VERSION 5.8 ;
BUSBITCHARS "[]" ;
DIVIDERCHAR "/" ;
UNITS
    DATABASE MICRONS 1000 ;
END UNITS

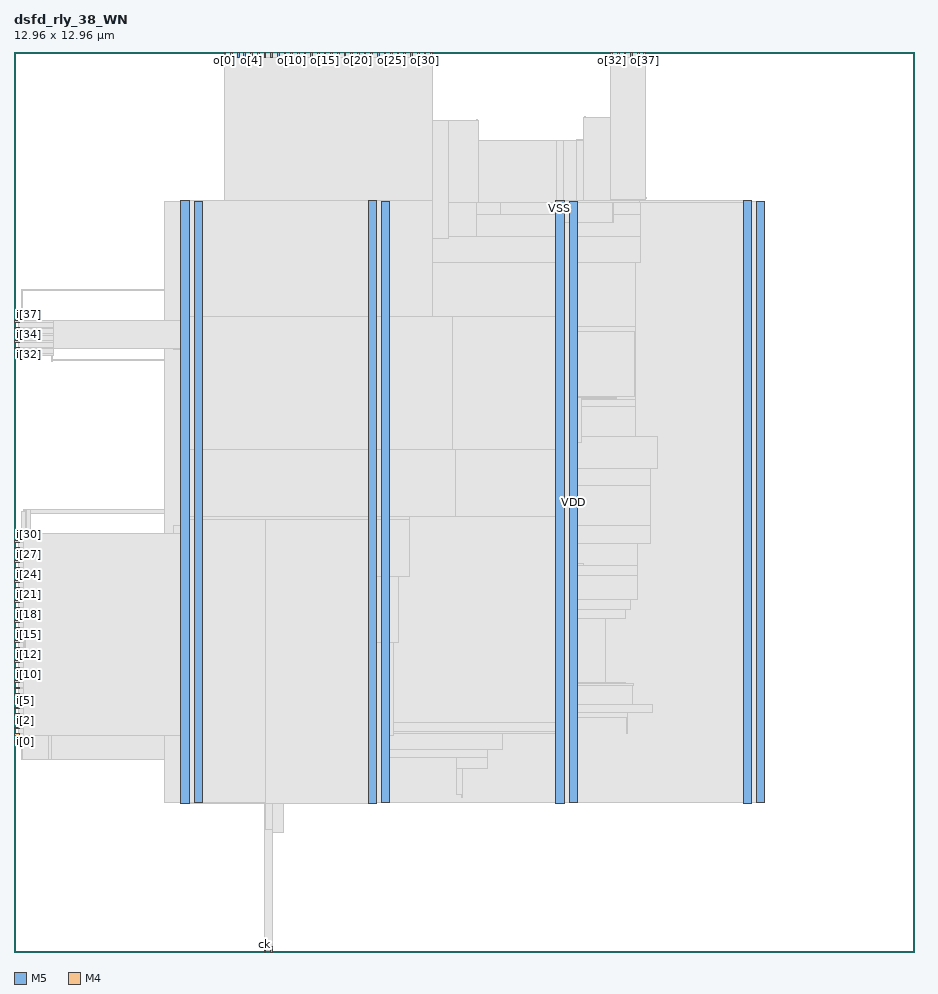
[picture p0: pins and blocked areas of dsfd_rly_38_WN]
MACRO dsfd_rly_38_WN
  FOREIGN dsfd_rly_38_WN 0 0 ;
  CLASS BLOCK ;
  SIZE 12.96 BY 12.96 ;
  PIN ck
    DIRECTION INPUT ;
    USE SIGNAL ;
    PORT
      LAYER M5 ;
        RECT  3.6 0 3.624 0.084 ;
    END
  END ck
  PIN i[0]
    DIRECTION INPUT ;
    USE SIGNAL ;
    PORT
      LAYER M4 ;
        RECT  0 3.024 0.084 3.048 ;
    END
  END i[0]
  PIN i[10]
    DIRECTION INPUT ;
    USE SIGNAL ;
    PORT
      LAYER M4 ;
        RECT  0 3.984 0.084 4.008 ;
    END
  END i[10]
  PIN i[11]
    DIRECTION INPUT ;
    USE SIGNAL ;
    PORT
      LAYER M4 ;
        RECT  0 4.08 0.084 4.104 ;
    END
  END i[11]
  PIN i[12]
    DIRECTION INPUT ;
    USE SIGNAL ;
    PORT
      LAYER M4 ;
        RECT  0 4.176 0.084 4.2 ;
    END
  END i[12]
  PIN i[13]
    DIRECTION INPUT ;
    USE SIGNAL ;
    PORT
      LAYER M4 ;
        RECT  0 4.272 0.084 4.296 ;
    END
  END i[13]
  PIN i[14]
    DIRECTION INPUT ;
    USE SIGNAL ;
    PORT
      LAYER M4 ;
        RECT  0 4.368 0.084 4.392 ;
    END
  END i[14]
  PIN i[15]
    DIRECTION INPUT ;
    USE SIGNAL ;
    PORT
      LAYER M4 ;
        RECT  0 4.464 0.084 4.488 ;
    END
  END i[15]
  PIN i[16]
    DIRECTION INPUT ;
    USE SIGNAL ;
    PORT
      LAYER M4 ;
        RECT  0 4.56 0.084 4.584 ;
    END
  END i[16]
  PIN i[17]
    DIRECTION INPUT ;
    USE SIGNAL ;
    PORT
      LAYER M4 ;
        RECT  0 4.656 0.084 4.68 ;
    END
  END i[17]
  PIN i[18]
    DIRECTION INPUT ;
    USE SIGNAL ;
    PORT
      LAYER M4 ;
        RECT  0 4.752 0.084 4.776 ;
    END
  END i[18]
  PIN i[19]
    DIRECTION INPUT ;
    USE SIGNAL ;
    PORT
      LAYER M4 ;
        RECT  0 4.848 0.084 4.872 ;
    END
  END i[19]
  PIN i[1]
    DIRECTION INPUT ;
    USE SIGNAL ;
    PORT
      LAYER M4 ;
        RECT  0 3.12 0.084 3.144 ;
    END
  END i[1]
  PIN i[20]
    DIRECTION INPUT ;
    USE SIGNAL ;
    PORT
      LAYER M4 ;
        RECT  0 4.944 0.084 4.968 ;
    END
  END i[20]
  PIN i[21]
    DIRECTION INPUT ;
    USE SIGNAL ;
    PORT
      LAYER M4 ;
        RECT  0 5.04 0.084 5.064 ;
    END
  END i[21]
  PIN i[22]
    DIRECTION INPUT ;
    USE SIGNAL ;
    PORT
      LAYER M4 ;
        RECT  0 5.136 0.084 5.16 ;
    END
  END i[22]
  PIN i[23]
    DIRECTION INPUT ;
    USE SIGNAL ;
    PORT
      LAYER M4 ;
        RECT  0 5.232 0.084 5.256 ;
    END
  END i[23]
  PIN i[24]
    DIRECTION INPUT ;
    USE SIGNAL ;
    PORT
      LAYER M4 ;
        RECT  0 5.328 0.084 5.352 ;
    END
  END i[24]
  PIN i[25]
    DIRECTION INPUT ;
    USE SIGNAL ;
    PORT
      LAYER M4 ;
        RECT  0 5.424 0.084 5.448 ;
    END
  END i[25]
  PIN i[26]
    DIRECTION INPUT ;
    USE SIGNAL ;
    PORT
      LAYER M4 ;
        RECT  0 5.52 0.084 5.544 ;
    END
  END i[26]
  PIN i[27]
    DIRECTION INPUT ;
    USE SIGNAL ;
    PORT
      LAYER M4 ;
        RECT  0 5.616 0.084 5.64 ;
    END
  END i[27]
  PIN i[28]
    DIRECTION INPUT ;
    USE SIGNAL ;
    PORT
      LAYER M4 ;
        RECT  0 5.712 0.084 5.736 ;
    END
  END i[28]
  PIN i[29]
    DIRECTION INPUT ;
    USE SIGNAL ;
    PORT
      LAYER M4 ;
        RECT  0 5.808 0.084 5.832 ;
    END
  END i[29]
  PIN i[2]
    DIRECTION INPUT ;
    USE SIGNAL ;
    PORT
      LAYER M4 ;
        RECT  0 3.216 0.084 3.24 ;
    END
  END i[2]
  PIN i[30]
    DIRECTION INPUT ;
    USE SIGNAL ;
    PORT
      LAYER M4 ;
        RECT  0 5.904 0.084 5.928 ;
    END
  END i[30]
  PIN i[31]
    DIRECTION INPUT ;
    USE SIGNAL ;
    PORT
      LAYER M4 ;
        RECT  0 6 0.084 6.024 ;
    END
  END i[31]
  PIN i[32]
    DIRECTION INPUT ;
    USE SIGNAL ;
    PORT
      LAYER M4 ;
        RECT  0 8.592 0.084 8.616 ;
    END
  END i[32]
  PIN i[33]
    DIRECTION INPUT ;
    USE SIGNAL ;
    PORT
      LAYER M4 ;
        RECT  0 8.688 0.084 8.712 ;
    END
  END i[33]
  PIN i[34]
    DIRECTION INPUT ;
    USE SIGNAL ;
    PORT
      LAYER M4 ;
        RECT  0 8.784 0.084 8.808 ;
    END
  END i[34]
  PIN i[35]
    DIRECTION INPUT ;
    USE SIGNAL ;
    PORT
      LAYER M4 ;
        RECT  0 8.88 0.084 8.904 ;
    END
  END i[35]
  PIN i[36]
    DIRECTION INPUT ;
    USE SIGNAL ;
    PORT
      LAYER M4 ;
        RECT  0 8.976 0.084 9 ;
    END
  END i[36]
  PIN i[37]
    DIRECTION INPUT ;
    USE SIGNAL ;
    PORT
      LAYER M4 ;
        RECT  0 9.072 0.084 9.096 ;
    END
  END i[37]
  PIN i[3]
    DIRECTION INPUT ;
    USE SIGNAL ;
    PORT
      LAYER M4 ;
        RECT  0 3.312 0.084 3.336 ;
    END
  END i[3]
  PIN i[4]
    DIRECTION INPUT ;
    USE SIGNAL ;
    PORT
      LAYER M4 ;
        RECT  0 3.408 0.084 3.432 ;
    END
  END i[4]
  PIN i[5]
    DIRECTION INPUT ;
    USE SIGNAL ;
    PORT
      LAYER M4 ;
        RECT  0 3.504 0.084 3.528 ;
    END
  END i[5]
  PIN i[6]
    DIRECTION INPUT ;
    USE SIGNAL ;
    PORT
      LAYER M4 ;
        RECT  0 3.6 0.084 3.624 ;
    END
  END i[6]
  PIN i[7]
    DIRECTION INPUT ;
    USE SIGNAL ;
    PORT
      LAYER M4 ;
        RECT  0 3.696 0.084 3.72 ;
    END
  END i[7]
  PIN i[8]
    DIRECTION INPUT ;
    USE SIGNAL ;
    PORT
      LAYER M4 ;
        RECT  0 3.792 0.084 3.816 ;
    END
  END i[8]
  PIN i[9]
    DIRECTION INPUT ;
    USE SIGNAL ;
    PORT
      LAYER M4 ;
        RECT  0 3.888 0.084 3.912 ;
    END
  END i[9]
  PIN o[0]
    DIRECTION OUTPUT ;
    USE SIGNAL ;
    PORT
      LAYER M5 ;
        RECT  3.024 12.876 3.048 12.96 ;
    END
  END o[0]
  PIN o[10]
    DIRECTION OUTPUT ;
    USE SIGNAL ;
    PORT
      LAYER M5 ;
        RECT  3.984 12.876 4.008 12.96 ;
    END
  END o[10]
  PIN o[11]
    DIRECTION OUTPUT ;
    USE SIGNAL ;
    PORT
      LAYER M5 ;
        RECT  4.08 12.876 4.104 12.96 ;
    END
  END o[11]
  PIN o[12]
    DIRECTION OUTPUT ;
    USE SIGNAL ;
    PORT
      LAYER M5 ;
        RECT  4.176 12.876 4.2 12.96 ;
    END
  END o[12]
  PIN o[13]
    DIRECTION OUTPUT ;
    USE SIGNAL ;
    PORT
      LAYER M5 ;
        RECT  4.272 12.876 4.296 12.96 ;
    END
  END o[13]
  PIN o[14]
    DIRECTION OUTPUT ;
    USE SIGNAL ;
    PORT
      LAYER M5 ;
        RECT  4.368 12.876 4.392 12.96 ;
    END
  END o[14]
  PIN o[15]
    DIRECTION OUTPUT ;
    USE SIGNAL ;
    PORT
      LAYER M5 ;
        RECT  4.464 12.876 4.488 12.96 ;
    END
  END o[15]
  PIN o[16]
    DIRECTION OUTPUT ;
    USE SIGNAL ;
    PORT
      LAYER M5 ;
        RECT  4.56 12.876 4.584 12.96 ;
    END
  END o[16]
  PIN o[17]
    DIRECTION OUTPUT ;
    USE SIGNAL ;
    PORT
      LAYER M5 ;
        RECT  4.656 12.876 4.68 12.96 ;
    END
  END o[17]
  PIN o[18]
    DIRECTION OUTPUT ;
    USE SIGNAL ;
    PORT
      LAYER M5 ;
        RECT  4.752 12.876 4.776 12.96 ;
    END
  END o[18]
  PIN o[19]
    DIRECTION OUTPUT ;
    USE SIGNAL ;
    PORT
      LAYER M5 ;
        RECT  4.848 12.876 4.872 12.96 ;
    END
  END o[19]
  PIN o[1]
    DIRECTION OUTPUT ;
    USE SIGNAL ;
    PORT
      LAYER M5 ;
        RECT  3.12 12.876 3.144 12.96 ;
    END
  END o[1]
  PIN o[20]
    DIRECTION OUTPUT ;
    USE SIGNAL ;
    PORT
      LAYER M5 ;
        RECT  4.944 12.876 4.968 12.96 ;
    END
  END o[20]
  PIN o[21]
    DIRECTION OUTPUT ;
    USE SIGNAL ;
    PORT
      LAYER M5 ;
        RECT  5.04 12.876 5.064 12.96 ;
    END
  END o[21]
  PIN o[22]
    DIRECTION OUTPUT ;
    USE SIGNAL ;
    PORT
      LAYER M5 ;
        RECT  5.136 12.876 5.16 12.96 ;
    END
  END o[22]
  PIN o[23]
    DIRECTION OUTPUT ;
    USE SIGNAL ;
    PORT
      LAYER M5 ;
        RECT  5.232 12.876 5.256 12.96 ;
    END
  END o[23]
  PIN o[24]
    DIRECTION OUTPUT ;
    USE SIGNAL ;
    PORT
      LAYER M5 ;
        RECT  5.328 12.876 5.352 12.96 ;
    END
  END o[24]
  PIN o[25]
    DIRECTION OUTPUT ;
    USE SIGNAL ;
    PORT
      LAYER M5 ;
        RECT  5.424 12.876 5.448 12.96 ;
    END
  END o[25]
  PIN o[26]
    DIRECTION OUTPUT ;
    USE SIGNAL ;
    PORT
      LAYER M5 ;
        RECT  5.52 12.876 5.544 12.96 ;
    END
  END o[26]
  PIN o[27]
    DIRECTION OUTPUT ;
    USE SIGNAL ;
    PORT
      LAYER M5 ;
        RECT  5.616 12.876 5.64 12.96 ;
    END
  END o[27]
  PIN o[28]
    DIRECTION OUTPUT ;
    USE SIGNAL ;
    PORT
      LAYER M5 ;
        RECT  5.712 12.876 5.736 12.96 ;
    END
  END o[28]
  PIN o[29]
    DIRECTION OUTPUT ;
    USE SIGNAL ;
    PORT
      LAYER M5 ;
        RECT  5.808 12.876 5.832 12.96 ;
    END
  END o[29]
  PIN o[2]
    DIRECTION OUTPUT ;
    USE SIGNAL ;
    PORT
      LAYER M5 ;
        RECT  3.216 12.876 3.24 12.96 ;
    END
  END o[2]
  PIN o[30]
    DIRECTION OUTPUT ;
    USE SIGNAL ;
    PORT
      LAYER M5 ;
        RECT  5.904 12.876 5.928 12.96 ;
    END
  END o[30]
  PIN o[31]
    DIRECTION OUTPUT ;
    USE SIGNAL ;
    PORT
      LAYER M5 ;
        RECT  6 12.876 6.024 12.96 ;
    END
  END o[31]
  PIN o[32]
    DIRECTION OUTPUT ;
    USE SIGNAL ;
    PORT
      LAYER M5 ;
        RECT  8.592 12.876 8.616 12.96 ;
    END
  END o[32]
  PIN o[33]
    DIRECTION OUTPUT ;
    USE SIGNAL ;
    PORT
      LAYER M5 ;
        RECT  8.688 12.876 8.712 12.96 ;
    END
  END o[33]
  PIN o[34]
    DIRECTION OUTPUT ;
    USE SIGNAL ;
    PORT
      LAYER M5 ;
        RECT  8.784 12.876 8.808 12.96 ;
    END
  END o[34]
  PIN o[35]
    DIRECTION OUTPUT ;
    USE SIGNAL ;
    PORT
      LAYER M5 ;
        RECT  8.88 12.876 8.904 12.96 ;
    END
  END o[35]
  PIN o[36]
    DIRECTION OUTPUT ;
    USE SIGNAL ;
    PORT
      LAYER M5 ;
        RECT  8.976 12.876 9 12.96 ;
    END
  END o[36]
  PIN o[37]
    DIRECTION OUTPUT ;
    USE SIGNAL ;
    PORT
      LAYER M5 ;
        RECT  9.072 12.876 9.096 12.96 ;
    END
  END o[37]
  PIN o[3]
    DIRECTION OUTPUT ;
    USE SIGNAL ;
    PORT
      LAYER M5 ;
        RECT  3.312 12.876 3.336 12.96 ;
    END
  END o[3]
  PIN o[4]
    DIRECTION OUTPUT ;
    USE SIGNAL ;
    PORT
      LAYER M5 ;
        RECT  3.408 12.876 3.432 12.96 ;
    END
  END o[4]
  PIN o[5]
    DIRECTION OUTPUT ;
    USE SIGNAL ;
    PORT
      LAYER M5 ;
        RECT  3.504 12.876 3.528 12.96 ;
    END
  END o[5]
  PIN o[6]
    DIRECTION OUTPUT ;
    USE SIGNAL ;
    PORT
      LAYER M5 ;
        RECT  3.6 12.876 3.624 12.96 ;
    END
  END o[6]
  PIN o[7]
    DIRECTION OUTPUT ;
    USE SIGNAL ;
    PORT
      LAYER M5 ;
        RECT  3.696 12.876 3.72 12.96 ;
    END
  END o[7]
  PIN o[8]
    DIRECTION OUTPUT ;
    USE SIGNAL ;
    PORT
      LAYER M5 ;
        RECT  3.792 12.876 3.816 12.96 ;
    END
  END o[8]
  PIN o[9]
    DIRECTION OUTPUT ;
    USE SIGNAL ;
    PORT
      LAYER M5 ;
        RECT  3.888 12.876 3.912 12.96 ;
    END
  END o[9]
  PIN rs
    DIRECTION INPUT ;
    USE SIGNAL ;
    PORT
      LAYER M5 ;
        RECT  3.696 0 3.72 0.084 ;
    END
  END rs
  PIN VDD
    DIRECTION INOUT ;
    USE POWER ;
    PORT
      LAYER M5 ;
        RECT  10.692 2.151 10.812 10.809 ;
        RECT  7.992 2.151 8.112 10.809 ;
        RECT  5.292 2.151 5.412 10.809 ;
        RECT  2.592 2.151 2.712 10.809 ;
    END
  END VDD
  PIN VSS
    DIRECTION INOUT ;
    USE GROUND ;
    PORT
      LAYER M5 ;
        RECT  10.5 2.137 10.62 10.823 ;
        RECT  7.8 2.137 7.92 10.823 ;
        RECT  5.1 2.137 5.22 10.823 ;
        RECT  2.4 2.137 2.52 10.823 ;
    END
  END VSS
  # OT_OBS_CLOSED layer=M5 d_um=1.536 added=7
  OBS
    LAYER RVTN ;
     RECT  2.16 2.16 10.8 2.295 ;
     RECT  2.16 2.565 10.8 2.835 ;
     RECT  2.16 3.105 10.8 3.375 ;
     RECT  2.16 3.645 10.8 3.915 ;
     RECT  2.16 4.185 10.8 4.455 ;
     RECT  2.16 4.725 10.8 4.995 ;
     RECT  2.16 5.265 10.8 5.535 ;
     RECT  2.16 5.805 10.8 6.075 ;
     RECT  2.16 6.345 10.8 6.615 ;
     RECT  2.16 6.885 10.8 7.155 ;
     RECT  2.16 7.425 10.8 7.695 ;
     RECT  2.16 7.965 10.8 8.235 ;
     RECT  2.16 8.505 10.8 8.775 ;
     RECT  2.16 9.045 10.8 9.315 ;
     RECT  2.16 9.585 10.8 9.855 ;
     RECT  2.16 10.125 10.8 10.395 ;
     RECT  2.16 10.665 10.8 10.8 ;
    LAYER RVTP ;
     RECT  2.16 2.295 10.8 2.565 ;
     RECT  2.16 2.835 10.8 3.105 ;
     RECT  2.16 3.375 10.8 3.645 ;
     RECT  2.16 3.915 10.8 4.185 ;
     RECT  2.16 4.455 10.8 4.725 ;
     RECT  2.16 4.995 10.8 5.265 ;
     RECT  2.16 5.535 10.8 5.805 ;
     RECT  2.16 6.075 10.8 6.345 ;
     RECT  2.16 6.615 10.8 6.885 ;
     RECT  2.16 7.155 10.8 7.425 ;
     RECT  2.16 7.695 10.8 7.965 ;
     RECT  2.16 8.235 10.8 8.505 ;
     RECT  2.16 8.775 10.8 9.045 ;
     RECT  2.16 9.315 10.8 9.585 ;
     RECT  2.16 9.855 10.8 10.125 ;
     RECT  2.16 10.395 10.8 10.665 ;
    LAYER M1 ;
     RECT  2.16 2.151 10.8 10.809 ;
    LAYER M2 ;
     RECT  0.103 6.318 0.139 6.336 ;
     RECT  0.139 5.616 0.175 6.372 ;
     RECT  0.175 5.202 0.239 6.372 ;
     RECT  0.239 5.202 0.275 5.22 ;
     RECT  0.103 2.772 0.499 3.132 ;
     RECT  0.499 2.772 0.535 3.294 ;
     RECT  0.535 2.772 2.16 3.942 ;
     RECT  0.239 6.318 2.16 6.372 ;
     RECT  0.535 8.514 2.16 8.532 ;
     RECT  0.103 9.522 2.16 9.54 ;
     RECT  2.16 2.151 10.8 10.809 ;
     RECT  10.8 2.421 10.812 10.539 ;
    LAYER M3 ;
     RECT  5.115 2.143 5.205 2.191 ;
     RECT  3.852 1.723 3.87 2.263 ;
     RECT  4.752 2.191 5.205 2.263 ;
     RECT  6.444 2.227 6.462 2.263 ;
     RECT  2.415 2.143 2.505 2.413 ;
     RECT  3.852 2.263 5.205 2.413 ;
     RECT  7.815 2.143 7.905 2.413 ;
     RECT  10.515 2.143 10.605 2.413 ;
     RECT  2.415 2.413 2.697 2.497 ;
     RECT  3.852 2.413 5.397 2.497 ;
     RECT  6.372 2.263 6.462 2.641 ;
     RECT  2.415 2.497 5.397 2.803 ;
     RECT  6.372 2.641 6.822 2.803 ;
     RECT  2.415 2.803 6.822 2.911 ;
     RECT  2.415 2.911 7.038 3.145 ;
     RECT  7.815 2.413 8.097 3.145 ;
     RECT  2.415 3.145 8.097 3.181 ;
     RECT  0.108 2.767 0.126 3.271 ;
     RECT  0.108 3.271 0.522 3.379 ;
     RECT  2.304 3.181 8.097 3.379 ;
     RECT  8.82 3.145 8.838 3.379 ;
     RECT  0.108 3.379 0.558 3.437 ;
     RECT  2.304 3.379 8.838 3.451 ;
     RECT  2.304 3.451 9.198 3.569 ;
     RECT  2.304 3.569 8.91 3.869 ;
     RECT  2.304 3.869 8.802 3.875 ;
     RECT  0.504 3.437 0.558 4.109 ;
     RECT  2.304 3.875 8.514 4.801 ;
     RECT  2.304 4.801 8.802 4.927 ;
     RECT  2.304 4.927 8.874 5.071 ;
     RECT  0.324 4.363 0.342 5.179 ;
     RECT  0.252 5.179 0.342 5.197 ;
     RECT  2.304 5.071 8.982 5.419 ;
     RECT  0.18 5.197 0.342 5.515 ;
     RECT  0.108 5.515 0.342 5.549 ;
     RECT  2.268 5.419 8.982 5.567 ;
     RECT  2.304 5.567 8.982 5.881 ;
     RECT  0.108 5.549 0.27 6.029 ;
     RECT  2.304 5.881 9.162 6.143 ;
     RECT  0.108 6.029 0.162 6.341 ;
     RECT  0.144 6.341 0.162 6.377 ;
     RECT  2.415 6.143 9.162 6.719 ;
     RECT  2.415 6.719 6.894 6.845 ;
     RECT  7.632 6.719 9.162 6.961 ;
     RECT  7.632 6.961 9.27 7.421 ;
     RECT  3.744 6.845 6.894 7.771 ;
     RECT  3.528 7.771 6.894 7.861 ;
     RECT  7.632 7.421 8.946 7.861 ;
     RECT  2.415 6.845 2.697 7.963 ;
     RECT  3.528 7.861 8.946 7.963 ;
     RECT  2.415 7.963 8.946 7.997 ;
     RECT  0.54 8.509 0.558 8.621 ;
     RECT  2.415 7.997 8.097 8.683 ;
     RECT  2.304 8.683 8.097 8.735 ;
     RECT  2.34 8.735 8.097 8.941 ;
     RECT  8.928 7.997 8.946 8.941 ;
     RECT  2.34 8.941 8.946 9.005 ;
     RECT  0.108 8.875 0.126 9.545 ;
     RECT  2.415 9.005 8.946 9.931 ;
     RECT  2.415 9.931 9.018 10.301 ;
     RECT  2.415 10.301 5.814 10.547 ;
     RECT  10.515 2.413 10.797 10.547 ;
     RECT  6.66 10.301 9.018 10.625 ;
     RECT  3.384 10.547 5.814 10.781 ;
     RECT  2.415 10.547 2.505 10.817 ;
     RECT  7.815 10.625 9.018 10.817 ;
     RECT  10.515 10.547 10.605 10.817 ;
     RECT  6.66 10.625 7.002 10.829 ;
     RECT  8.1 10.817 9.018 11.405 ;
     RECT  3.528 10.781 5.814 11.453 ;
     RECT  8.1 11.405 8.55 11.453 ;
     RECT  5.4 11.453 5.418 11.501 ;
     RECT  8.1 11.453 8.226 11.693 ;
     RECT  6.66 10.829 6.678 11.981 ;
     RECT  8.208 11.693 8.226 12.029 ;
     RECT  3.528 11.453 4.59 12.619 ;
     RECT  3.528 12.619 4.95 12.715 ;
     RECT  3.528 12.715 5.094 12.845 ;
    LAYER M4 ;
     RECT  0.084 3.024 0.137 3.048 ;
     RECT  0.06 3.048 0.137 3.12 ;
     RECT  0.084 3.12 0.137 3.144 ;
     RECT  0.06 3.144 0.137 3.216 ;
     RECT  0.084 3.216 0.137 3.24 ;
     RECT  0.06 3.24 0.137 3.312 ;
     RECT  0.084 3.312 0.137 3.336 ;
     RECT  0.06 3.336 0.137 3.408 ;
     RECT  0.084 3.408 0.137 3.432 ;
     RECT  0.06 3.432 0.137 3.504 ;
     RECT  0.084 3.504 0.137 3.528 ;
     RECT  0.06 3.528 0.137 3.6 ;
     RECT  0.084 3.6 0.137 3.624 ;
     RECT  0.06 3.624 0.137 3.696 ;
     RECT  0.084 3.696 0.137 3.72 ;
     RECT  0.06 3.72 0.137 3.792 ;
     RECT  0.084 3.792 0.137 3.816 ;
     RECT  0.06 3.816 0.137 3.888 ;
     RECT  0.084 3.888 0.137 3.912 ;
     RECT  0.06 3.912 0.137 3.984 ;
     RECT  0.084 3.984 0.137 4.008 ;
     RECT  0.06 4.008 0.137 4.08 ;
     RECT  0.084 4.08 0.137 4.104 ;
     RECT  0.06 4.104 0.137 4.176 ;
     RECT  0.084 4.176 0.137 4.2 ;
     RECT  0.06 4.2 0.137 4.272 ;
     RECT  0.084 4.272 0.137 4.296 ;
     RECT  0.06 4.296 0.137 4.368 ;
     RECT  0.084 4.368 0.137 4.392 ;
     RECT  0.06 4.392 0.137 4.464 ;
     RECT  0.084 4.464 0.137 4.488 ;
     RECT  0.06 4.488 0.137 4.56 ;
     RECT  0.084 4.56 0.137 4.584 ;
     RECT  0.06 4.584 0.137 4.656 ;
     RECT  0.084 4.656 0.137 4.68 ;
     RECT  0.06 4.68 0.137 4.752 ;
     RECT  0.084 4.752 0.137 4.776 ;
     RECT  0.06 4.776 0.137 4.848 ;
     RECT  0.084 4.848 0.137 4.872 ;
     RECT  0.06 4.872 0.137 4.944 ;
     RECT  0.084 4.944 0.137 4.968 ;
     RECT  0.06 4.968 0.137 5.04 ;
     RECT  0.084 5.04 0.137 5.064 ;
     RECT  0.06 5.064 0.137 5.136 ;
     RECT  0.084 5.136 0.137 5.16 ;
     RECT  0.06 5.16 0.137 5.232 ;
     RECT  0.084 5.232 0.137 5.256 ;
     RECT  0.06 5.256 0.137 5.328 ;
     RECT  0.084 5.328 0.137 5.352 ;
     RECT  0.06 5.352 0.137 5.424 ;
     RECT  0.084 5.424 0.137 5.448 ;
     RECT  0.06 5.448 0.137 5.52 ;
     RECT  0.084 5.52 0.137 5.544 ;
     RECT  0.06 5.544 0.137 5.616 ;
     RECT  0.084 5.616 0.137 5.64 ;
     RECT  0.06 5.64 0.137 5.712 ;
     RECT  0.084 5.712 0.137 5.736 ;
     RECT  0.06 5.736 0.137 5.808 ;
     RECT  0.084 5.808 0.137 5.832 ;
     RECT  0.06 5.832 0.137 5.904 ;
     RECT  0.084 5.904 0.137 5.928 ;
     RECT  0.06 5.928 0.137 6 ;
     RECT  0.084 6 0.137 6.024 ;
     RECT  0.084 8.592 0.569 8.616 ;
     RECT  0.06 8.616 0.569 8.688 ;
     RECT  0.084 8.688 0.569 8.712 ;
     RECT  0.06 8.712 0.569 8.784 ;
     RECT  0.084 8.784 0.569 8.808 ;
     RECT  0.06 8.808 0.569 8.88 ;
     RECT  0.084 8.88 0.569 8.904 ;
     RECT  0.06 8.904 0.569 8.976 ;
     RECT  0.084 8.976 0.569 9 ;
     RECT  0.06 9 0.569 9.072 ;
     RECT  0.084 9.072 0.569 9.096 ;
     RECT  0.137 3.12 2.408 6.024 ;
     RECT  0.569 8.688 2.408 9.096 ;
     RECT  2.408 2.148 2.512 10.812 ;
     RECT  2.512 2.208 2.704 10.776 ;
     RECT  2.704 10.272 3.589 10.776 ;
     RECT  2.704 2.208 3.685 6.84 ;
     RECT  3.589 10.272 3.74 10.824 ;
     RECT  3.685 1.728 3.881 6.84 ;
     RECT  3.881 2.208 3.913 6.84 ;
     RECT  2.704 7.968 3.913 9.096 ;
     RECT  3.74 10.272 3.973 11.448 ;
     RECT  3.397 12.816 3.973 12.84 ;
     RECT  3.913 2.208 5.108 9.096 ;
     RECT  3.973 10.272 5.108 12.84 ;
     RECT  5.108 2.148 5.126 12.84 ;
     RECT  5.126 2.148 5.212 12.792 ;
     RECT  5.212 2.418 5.404 12.792 ;
     RECT  5.404 3.12 5.465 9.144 ;
     RECT  5.404 10.272 5.699 12.792 ;
     RECT  5.699 10.272 6.257 11.976 ;
     RECT  6.257 10.8 6.689 11.976 ;
     RECT  5.465 3.312 7.808 9.144 ;
     RECT  6.689 10.8 7.808 11.688 ;
     RECT  7.808 2.148 7.912 11.688 ;
     RECT  7.912 2.418 8.104 11.688 ;
     RECT  8.104 7.344 8.165 7.992 ;
     RECT  8.104 10.512 8.197 11.688 ;
     RECT  8.104 5.568 8.201 5.592 ;
     RECT  8.197 10.512 8.627 12.024 ;
     RECT  8.165 7.968 8.669 7.992 ;
     RECT  8.627 10.8 8.723 12.024 ;
     RECT  8.723 10.8 8.819 11.448 ;
     RECT  8.104 3.84 8.921 3.864 ;
     RECT  8.819 10.8 9.029 11.4 ;
     RECT  9.029 10.8 9.037 10.872 ;
     RECT  9.037 10.848 9.107 10.872 ;
     RECT  10.508 2.148 10.612 10.812 ;
     RECT  10.612 2.418 10.804 10.542 ;
    LAYER M5 ;
     RECT  3.624 0.016 3.696 0.084 ;
     RECT  3.6 0.084 3.72 1.763 ;
     RECT  2.4 2.137 2.52 2.151 ;
     RECT  3.6 1.763 3.624 2.151 ;
     RECT  5.1 2.137 5.22 2.151 ;
     RECT  7.8 2.137 7.92 2.151 ;
     RECT  10.5 2.137 10.62 2.151 ;
     RECT  5.1 2.151 5.412 4.453 ;
     RECT  0.144 4.213 0.168 4.499 ;
     RECT  5.1 4.453 5.544 5.413 ;
     RECT  2.4 2.151 3.624 6.229 ;
     RECT  5.1 5.413 5.688 6.229 ;
     RECT  2.4 6.229 5.688 6.277 ;
     RECT  2.4 6.277 6.36 7.235 ;
     RECT  2.4 7.235 6.312 9.155 ;
     RECT  7.8 2.151 8.112 10.501 ;
     RECT  7.8 10.501 8.616 10.789 ;
     RECT  10.5 2.151 10.812 10.809 ;
     RECT  2.4 9.155 6.024 10.823 ;
     RECT  7.8 10.789 9 10.823 ;
     RECT  10.5 10.809 10.62 10.823 ;
     RECT  8.592 10.823 9 10.837 ;
     RECT  3.024 10.823 6.024 12.876 ;
     RECT  3.048 12.876 3.12 12.944 ;
     RECT  3.144 12.876 3.216 12.944 ;
     RECT  3.24 12.876 3.312 12.944 ;
     RECT  3.336 12.876 3.408 12.944 ;
     RECT  3.432 12.876 3.504 12.944 ;
     RECT  3.528 12.876 3.6 12.944 ;
     RECT  3.624 12.876 3.696 12.944 ;
     RECT  3.72 12.876 3.792 12.944 ;
     RECT  3.816 12.876 3.888 12.944 ;
     RECT  3.912 12.876 3.984 12.944 ;
     RECT  4.008 12.876 4.08 12.944 ;
     RECT  4.104 12.876 4.176 12.944 ;
     RECT  4.2 12.876 4.272 12.944 ;
     RECT  4.296 12.876 4.368 12.944 ;
     RECT  4.392 12.876 4.464 12.944 ;
     RECT  4.488 12.876 4.56 12.944 ;
     RECT  4.584 12.876 4.656 12.944 ;
     RECT  4.68 12.876 4.752 12.944 ;
     RECT  4.776 12.876 4.848 12.944 ;
     RECT  4.872 12.876 4.944 12.944 ;
     RECT  4.968 12.876 5.04 12.944 ;
     RECT  5.064 12.876 5.136 12.944 ;
     RECT  5.16 12.876 5.232 12.944 ;
     RECT  5.256 12.876 5.328 12.944 ;
     RECT  5.352 12.876 5.424 12.944 ;
     RECT  5.448 12.876 5.52 12.944 ;
     RECT  5.544 12.876 5.616 12.944 ;
     RECT  5.64 12.876 5.712 12.944 ;
     RECT  5.736 12.876 5.808 12.944 ;
     RECT  5.832 12.876 5.904 12.944 ;
     RECT  5.928 12.876 6 12.944 ;
     RECT  8.592 10.837 9.096 12.876 ;
     RECT  8.616 12.876 8.688 12.944 ;
     RECT  8.712 12.876 8.784 12.944 ;
     RECT  8.808 12.876 8.88 12.944 ;
     RECT  8.904 12.876 8.976 12.944 ;
     RECT  9 12.876 9.072 12.944 ;
     RECT  3.624 1.763 3.72 2.137 ;
     RECT  2.52 2.137 3.6 2.151 ;
     RECT  3.624 2.137 5.1 6.229 ;
     RECT  6.36 6.277 7.8 7.235 ;
     RECT  6.312 7.235 7.8 9.155 ;
     RECT  9 10.789 10.5 10.823 ;
     RECT  9 10.823 9.096 10.837 ;
  END
END dsfd_rly_38_WN
END LIBRARY
